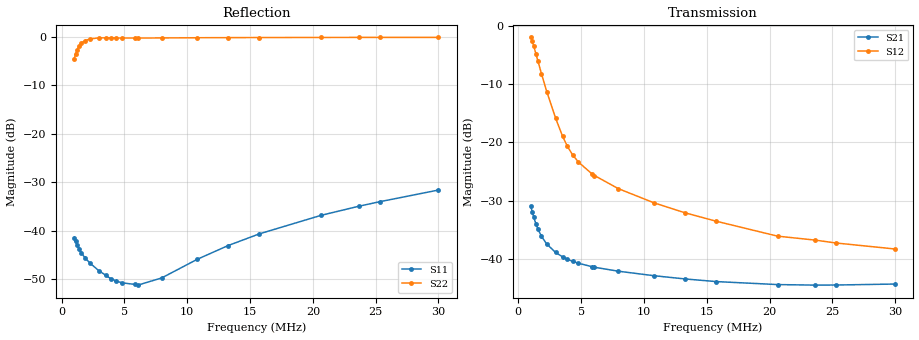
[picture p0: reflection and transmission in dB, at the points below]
! ListType=Log
!!FT114A-31 10T CMR
# MHZ S RI R 50
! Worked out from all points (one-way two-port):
!   101 points, 1 MHz to 30 MHz, reference 50 ohm
!   highest |S21| = -30.98 dB at 1 MHz (marker M1); lowest = -44.5 dB at 23.64 MHz (marker M2)
!   lowest |S11| = -51.2 dB at 6.066 MHz (marker M3), VSWR 1.01, Z = 50.2 + j0.199 ohm
!   |S11| at or under -10 dB: start of sweep to end of sweep
!   |S22| runs from -4.6 to -0.1 dB; largest |S21 - S12| = 0.78
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1  -0.00202 0.00823  0.00715 -0.0273  0.6466 -0.4725  0.3537 0.472
1.107423  -0.00186 0.00756  0.00691 -0.0244  0.556 -0.4906  0.4443 0.49
1.226386  -0.00171 0.00698  0.0068 -0.0218  0.4616 -0.4915  0.5386 0.4909
1.405116  -0.00159 0.00627  0.0068 -0.0187  0.3415 -0.4657  0.6587 0.465
1.556058  -0.00143 0.0058  0.00686 -0.0167  0.2626 -0.4303  0.7374 0.4296
1.844513  -0.00117 0.00515  0.00701 -0.0139  0.1608 -0.3547  0.8391 0.354
2.262086  -0.000884 0.00456  0.00718 -0.0113  0.0849 -0.2608  0.9149 0.2601
2.969469  -0.000338 0.00386  0.0073 -0.00865  0.0384 -0.1571  0.9615 0.1561
3.519937  9.36e-05 0.00348  0.00732 -0.00737  0.0303 -0.1091  0.9696 0.1079
3.89806  0.000362 0.0032  0.0073 -0.0067  0.03 -0.088  0.9699 0.0867
4.316802  0.000699 0.00297  0.00728 -0.00611  0.0306 -0.0722  0.9692 0.0705
4.780527  0.00108 0.00271  0.00726 -0.00557  0.0311 -0.0603  0.9688 0.0583
5.862773  0.00183 0.00212  0.00717 -0.00464  0.0307 -0.0441  0.9691 0.0414
6.065607  0.00192 0.00198  0.00715 -0.0045  0.0304 -0.0421  0.9694 0.0392
7.9624  0.00316 0.000838  0.00697 -0.00353  0.0269 -0.0297  0.9729 0.0249
10.81396  0.00499 -0.00106  0.00664 -0.00263  0.0222 -0.0205  0.9774 0.0119
13.2621  0.00639 -0.003  0.00639 -0.00203  0.0191 -0.0159  0.9801 0.00327
15.72057  0.00772 -0.00517  0.00619 -0.00148  0.0171 -0.0123  0.9821 -0.00495
20.63659  0.0101 -0.0103  0.00597 -0.000551  0.0142 -0.00656  0.9838 -0.0209
23.6441  0.0113 -0.0139  0.00593 -5.97e-05  0.0137 -0.00461  0.9846 -0.0322
25.30843  0.0119 -0.016  0.00594 0.000187  0.0132 -0.00348  0.9845 -0.0387
30  0.013 -0.0229  0.006 0.00084  0.0121 -0.000789  0.984 -0.0582
